# Generated deterministically by seda-macro-lef-normalizer-v1; recipe orfs-asap7-fakeram-m4-v1.
VERSION 5.8 ;
BUSBITCHARS "[]" ;
DIVIDERCHAR "/" ;

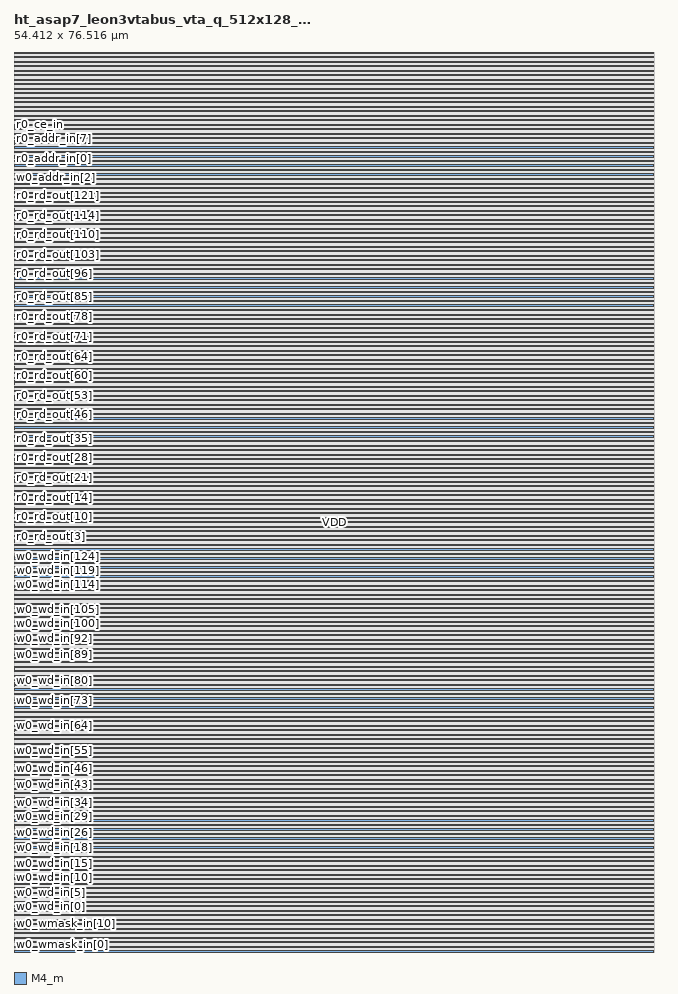
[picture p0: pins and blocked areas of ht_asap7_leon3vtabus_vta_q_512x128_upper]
MACRO ht_asap7_leon3vtabus_vta_q_512x128_upper
  FOREIGN ht_asap7_leon3vtabus_vta_q_512x128_upper 0 0 ;
  CLASS BLOCK ;
  ORIGIN 0 0 ;
  SIZE 54.412 BY 76.516 ;
  SYMMETRY X Y R90 ;
  PIN w0_wmask_in[0]
    DIRECTION INPUT ;
    USE SIGNAL ;
    SHAPE ABUTMENT ;
    PORT
      LAYER M4_m ;
      RECT 0 0.048 0.024 0.072 ;
    END
  END w0_wmask_in[0]
  PIN w0_wmask_in[1]
    DIRECTION INPUT ;
    USE SIGNAL ;
    SHAPE ABUTMENT ;
    PORT
      LAYER M4_m ;
      RECT 0 0.288 0.024 0.312 ;
    END
  END w0_wmask_in[1]
  PIN w0_wmask_in[2]
    DIRECTION INPUT ;
    USE SIGNAL ;
    SHAPE ABUTMENT ;
    PORT
      LAYER M4_m ;
      RECT 0 0.528 0.024 0.552 ;
    END
  END w0_wmask_in[2]
  PIN w0_wmask_in[3]
    DIRECTION INPUT ;
    USE SIGNAL ;
    SHAPE ABUTMENT ;
    PORT
      LAYER M4_m ;
      RECT 0 0.768 0.024 0.792 ;
    END
  END w0_wmask_in[3]
  PIN w0_wmask_in[4]
    DIRECTION INPUT ;
    USE SIGNAL ;
    SHAPE ABUTMENT ;
    PORT
      LAYER M4_m ;
      RECT 0 1.008 0.024 1.032 ;
    END
  END w0_wmask_in[4]
  PIN w0_wmask_in[5]
    DIRECTION INPUT ;
    USE SIGNAL ;
    SHAPE ABUTMENT ;
    PORT
      LAYER M4_m ;
      RECT 0 1.248 0.024 1.272 ;
    END
  END w0_wmask_in[5]
  PIN w0_wmask_in[6]
    DIRECTION INPUT ;
    USE SIGNAL ;
    SHAPE ABUTMENT ;
    PORT
      LAYER M4_m ;
      RECT 0 1.488 0.024 1.512 ;
    END
  END w0_wmask_in[6]
  PIN w0_wmask_in[7]
    DIRECTION INPUT ;
    USE SIGNAL ;
    SHAPE ABUTMENT ;
    PORT
      LAYER M4_m ;
      RECT 0 1.728 0.024 1.752 ;
    END
  END w0_wmask_in[7]
  PIN w0_wmask_in[8]
    DIRECTION INPUT ;
    USE SIGNAL ;
    SHAPE ABUTMENT ;
    PORT
      LAYER M4_m ;
      RECT 0 1.968 0.024 1.992 ;
    END
  END w0_wmask_in[8]
  PIN w0_wmask_in[9]
    DIRECTION INPUT ;
    USE SIGNAL ;
    SHAPE ABUTMENT ;
    PORT
      LAYER M4_m ;
      RECT 0 2.208 0.024 2.232 ;
    END
  END w0_wmask_in[9]
  PIN w0_wmask_in[10]
    DIRECTION INPUT ;
    USE SIGNAL ;
    SHAPE ABUTMENT ;
    PORT
      LAYER M4_m ;
      RECT 0 2.448 0.024 2.472 ;
    END
  END w0_wmask_in[10]
  PIN w0_wmask_in[11]
    DIRECTION INPUT ;
    USE SIGNAL ;
    SHAPE ABUTMENT ;
    PORT
      LAYER M4_m ;
      RECT 0 2.688 0.024 2.712 ;
    END
  END w0_wmask_in[11]
  PIN w0_wmask_in[12]
    DIRECTION INPUT ;
    USE SIGNAL ;
    SHAPE ABUTMENT ;
    PORT
      LAYER M4_m ;
      RECT 0 2.928 0.024 2.952 ;
    END
  END w0_wmask_in[12]
  PIN w0_wmask_in[13]
    DIRECTION INPUT ;
    USE SIGNAL ;
    SHAPE ABUTMENT ;
    PORT
      LAYER M4_m ;
      RECT 0 3.168 0.024 3.192 ;
    END
  END w0_wmask_in[13]
  PIN w0_wmask_in[14]
    DIRECTION INPUT ;
    USE SIGNAL ;
    SHAPE ABUTMENT ;
    PORT
      LAYER M4_m ;
      RECT 0 3.408 0.024 3.432 ;
    END
  END w0_wmask_in[14]
  PIN w0_wmask_in[15]
    DIRECTION INPUT ;
    USE SIGNAL ;
    SHAPE ABUTMENT ;
    PORT
      LAYER M4_m ;
      RECT 0 3.648 0.024 3.672 ;
    END
  END w0_wmask_in[15]
  PIN w0_wd_in[0]
    DIRECTION INPUT ;
    USE SIGNAL ;
    SHAPE ABUTMENT ;
    PORT
      LAYER M4_m ;
      RECT 0 3.888 0.024 3.912 ;
    END
  END w0_wd_in[0]
  PIN w0_wd_in[1]
    DIRECTION INPUT ;
    USE SIGNAL ;
    SHAPE ABUTMENT ;
    PORT
      LAYER M4_m ;
      RECT 0 4.128 0.024 4.152 ;
    END
  END w0_wd_in[1]
  PIN w0_wd_in[2]
    DIRECTION INPUT ;
    USE SIGNAL ;
    SHAPE ABUTMENT ;
    PORT
      LAYER M4_m ;
      RECT 0 4.368 0.024 4.392 ;
    END
  END w0_wd_in[2]
  PIN w0_wd_in[3]
    DIRECTION INPUT ;
    USE SIGNAL ;
    SHAPE ABUTMENT ;
    PORT
      LAYER M4_m ;
      RECT 0 4.608 0.024 4.632 ;
    END
  END w0_wd_in[3]
  PIN w0_wd_in[4]
    DIRECTION INPUT ;
    USE SIGNAL ;
    SHAPE ABUTMENT ;
    PORT
      LAYER M4_m ;
      RECT 0 4.848 0.024 4.872 ;
    END
  END w0_wd_in[4]
  PIN w0_wd_in[5]
    DIRECTION INPUT ;
    USE SIGNAL ;
    SHAPE ABUTMENT ;
    PORT
      LAYER M4_m ;
      RECT 0 5.088 0.024 5.112 ;
    END
  END w0_wd_in[5]
  PIN w0_wd_in[6]
    DIRECTION INPUT ;
    USE SIGNAL ;
    SHAPE ABUTMENT ;
    PORT
      LAYER M4_m ;
      RECT 0 5.328 0.024 5.352 ;
    END
  END w0_wd_in[6]
  PIN w0_wd_in[7]
    DIRECTION INPUT ;
    USE SIGNAL ;
    SHAPE ABUTMENT ;
    PORT
      LAYER M4_m ;
      RECT 0 5.568 0.024 5.592 ;
    END
  END w0_wd_in[7]
  PIN w0_wd_in[8]
    DIRECTION INPUT ;
    USE SIGNAL ;
    SHAPE ABUTMENT ;
    PORT
      LAYER M4_m ;
      RECT 0 5.808 0.024 5.832 ;
    END
  END w0_wd_in[8]
  PIN w0_wd_in[9]
    DIRECTION INPUT ;
    USE SIGNAL ;
    SHAPE ABUTMENT ;
    PORT
      LAYER M4_m ;
      RECT 0 6.048 0.024 6.072 ;
    END
  END w0_wd_in[9]
  PIN w0_wd_in[10]
    DIRECTION INPUT ;
    USE SIGNAL ;
    SHAPE ABUTMENT ;
    PORT
      LAYER M4_m ;
      RECT 0 6.288 0.024 6.312 ;
    END
  END w0_wd_in[10]
  PIN w0_wd_in[11]
    DIRECTION INPUT ;
    USE SIGNAL ;
    SHAPE ABUTMENT ;
    PORT
      LAYER M4_m ;
      RECT 0 6.528 0.024 6.552 ;
    END
  END w0_wd_in[11]
  PIN w0_wd_in[12]
    DIRECTION INPUT ;
    USE SIGNAL ;
    SHAPE ABUTMENT ;
    PORT
      LAYER M4_m ;
      RECT 0 6.768 0.024 6.792 ;
    END
  END w0_wd_in[12]
  PIN w0_wd_in[13]
    DIRECTION INPUT ;
    USE SIGNAL ;
    SHAPE ABUTMENT ;
    PORT
      LAYER M4_m ;
      RECT 0 7.008 0.024 7.032 ;
    END
  END w0_wd_in[13]
  PIN w0_wd_in[14]
    DIRECTION INPUT ;
    USE SIGNAL ;
    SHAPE ABUTMENT ;
    PORT
      LAYER M4_m ;
      RECT 0 7.248 0.024 7.272 ;
    END
  END w0_wd_in[14]
  PIN w0_wd_in[15]
    DIRECTION INPUT ;
    USE SIGNAL ;
    SHAPE ABUTMENT ;
    PORT
      LAYER M4_m ;
      RECT 0 7.488 0.024 7.512 ;
    END
  END w0_wd_in[15]
  PIN w0_wd_in[16]
    DIRECTION INPUT ;
    USE SIGNAL ;
    SHAPE ABUTMENT ;
    PORT
      LAYER M4_m ;
      RECT 0 7.728 0.024 7.752 ;
    END
  END w0_wd_in[16]
  PIN w0_wd_in[17]
    DIRECTION INPUT ;
    USE SIGNAL ;
    SHAPE ABUTMENT ;
    PORT
      LAYER M4_m ;
      RECT 0 7.968 0.024 7.992 ;
    END
  END w0_wd_in[17]
  PIN w0_wd_in[18]
    DIRECTION INPUT ;
    USE SIGNAL ;
    SHAPE ABUTMENT ;
    PORT
      LAYER M4_m ;
      RECT 0 8.208 0.024 8.232 ;
    END
  END w0_wd_in[18]
  PIN w0_wd_in[19]
    DIRECTION INPUT ;
    USE SIGNAL ;
    SHAPE ABUTMENT ;
    PORT
      LAYER M4_m ;
      RECT 0 8.448 0.024 8.472 ;
    END
  END w0_wd_in[19]
  PIN w0_wd_in[20]
    DIRECTION INPUT ;
    USE SIGNAL ;
    SHAPE ABUTMENT ;
    PORT
      LAYER M4_m ;
      RECT 0 8.688 0.024 8.712 ;
    END
  END w0_wd_in[20]
  PIN w0_wd_in[21]
    DIRECTION INPUT ;
    USE SIGNAL ;
    SHAPE ABUTMENT ;
    PORT
      LAYER M4_m ;
      RECT 0 8.928 0.024 8.952 ;
    END
  END w0_wd_in[21]
  PIN w0_wd_in[22]
    DIRECTION INPUT ;
    USE SIGNAL ;
    SHAPE ABUTMENT ;
    PORT
      LAYER M4_m ;
      RECT 0 9.168 0.024 9.192 ;
    END
  END w0_wd_in[22]
  PIN w0_wd_in[23]
    DIRECTION INPUT ;
    USE SIGNAL ;
    SHAPE ABUTMENT ;
    PORT
      LAYER M4_m ;
      RECT 0 9.408 0.024 9.432 ;
    END
  END w0_wd_in[23]
  PIN w0_wd_in[24]
    DIRECTION INPUT ;
    USE SIGNAL ;
    SHAPE ABUTMENT ;
    PORT
      LAYER M4_m ;
      RECT 0 9.648 0.024 9.672 ;
    END
  END w0_wd_in[24]
  PIN w0_wd_in[25]
    DIRECTION INPUT ;
    USE SIGNAL ;
    SHAPE ABUTMENT ;
    PORT
      LAYER M4_m ;
      RECT 0 9.888 0.024 9.912 ;
    END
  END w0_wd_in[25]
  PIN w0_wd_in[26]
    DIRECTION INPUT ;
    USE SIGNAL ;
    SHAPE ABUTMENT ;
    PORT
      LAYER M4_m ;
      RECT 0 10.128 0.024 10.152 ;
    END
  END w0_wd_in[26]
  PIN w0_wd_in[27]
    DIRECTION INPUT ;
    USE SIGNAL ;
    SHAPE ABUTMENT ;
    PORT
      LAYER M4_m ;
      RECT 0 10.368 0.024 10.392 ;
    END
  END w0_wd_in[27]
  PIN w0_wd_in[28]
    DIRECTION INPUT ;
    USE SIGNAL ;
    SHAPE ABUTMENT ;
    PORT
      LAYER M4_m ;
      RECT 0 10.608 0.024 10.632 ;
    END
  END w0_wd_in[28]
  PIN w0_wd_in[29]
    DIRECTION INPUT ;
    USE SIGNAL ;
    SHAPE ABUTMENT ;
    PORT
      LAYER M4_m ;
      RECT 0 10.848 0.024 10.872 ;
    END
  END w0_wd_in[29]
  PIN w0_wd_in[30]
    DIRECTION INPUT ;
    USE SIGNAL ;
    SHAPE ABUTMENT ;
    PORT
      LAYER M4_m ;
      RECT 0 11.088 0.024 11.112 ;
    END
  END w0_wd_in[30]
  PIN w0_wd_in[31]
    DIRECTION INPUT ;
    USE SIGNAL ;
    SHAPE ABUTMENT ;
    PORT
      LAYER M4_m ;
      RECT 0 11.328 0.024 11.352 ;
    END
  END w0_wd_in[31]
  PIN w0_wd_in[32]
    DIRECTION INPUT ;
    USE SIGNAL ;
    SHAPE ABUTMENT ;
    PORT
      LAYER M4_m ;
      RECT 0 11.568 0.024 11.592 ;
    END
  END w0_wd_in[32]
  PIN w0_wd_in[33]
    DIRECTION INPUT ;
    USE SIGNAL ;
    SHAPE ABUTMENT ;
    PORT
      LAYER M4_m ;
      RECT 0 11.808 0.024 11.832 ;
    END
  END w0_wd_in[33]
  PIN w0_wd_in[34]
    DIRECTION INPUT ;
    USE SIGNAL ;
    SHAPE ABUTMENT ;
    PORT
      LAYER M4_m ;
      RECT 0 12.048 0.024 12.072 ;
    END
  END w0_wd_in[34]
  PIN w0_wd_in[35]
    DIRECTION INPUT ;
    USE SIGNAL ;
    SHAPE ABUTMENT ;
    PORT
      LAYER M4_m ;
      RECT 0 12.288 0.024 12.312 ;
    END
  END w0_wd_in[35]
  PIN w0_wd_in[36]
    DIRECTION INPUT ;
    USE SIGNAL ;
    SHAPE ABUTMENT ;
    PORT
      LAYER M4_m ;
      RECT 0 12.528 0.024 12.552 ;
    END
  END w0_wd_in[36]
  PIN w0_wd_in[37]
    DIRECTION INPUT ;
    USE SIGNAL ;
    SHAPE ABUTMENT ;
    PORT
      LAYER M4_m ;
      RECT 0 12.768 0.024 12.792 ;
    END
  END w0_wd_in[37]
  PIN w0_wd_in[38]
    DIRECTION INPUT ;
    USE SIGNAL ;
    SHAPE ABUTMENT ;
    PORT
      LAYER M4_m ;
      RECT 0 13.008 0.024 13.032 ;
    END
  END w0_wd_in[38]
  PIN w0_wd_in[39]
    DIRECTION INPUT ;
    USE SIGNAL ;
    SHAPE ABUTMENT ;
    PORT
      LAYER M4_m ;
      RECT 0 13.248 0.024 13.272 ;
    END
  END w0_wd_in[39]
  PIN w0_wd_in[40]
    DIRECTION INPUT ;
    USE SIGNAL ;
    SHAPE ABUTMENT ;
    PORT
      LAYER M4_m ;
      RECT 0 13.488 0.024 13.512 ;
    END
  END w0_wd_in[40]
  PIN w0_wd_in[41]
    DIRECTION INPUT ;
    USE SIGNAL ;
    SHAPE ABUTMENT ;
    PORT
      LAYER M4_m ;
      RECT 0 13.728 0.024 13.752 ;
    END
  END w0_wd_in[41]
  PIN w0_wd_in[42]
    DIRECTION INPUT ;
    USE SIGNAL ;
    SHAPE ABUTMENT ;
    PORT
      LAYER M4_m ;
      RECT 0 13.968 0.024 13.992 ;
    END
  END w0_wd_in[42]
  PIN w0_wd_in[43]
    DIRECTION INPUT ;
    USE SIGNAL ;
    SHAPE ABUTMENT ;
    PORT
      LAYER M4_m ;
      RECT 0 14.208 0.024 14.232 ;
    END
  END w0_wd_in[43]
  PIN w0_wd_in[44]
    DIRECTION INPUT ;
    USE SIGNAL ;
    SHAPE ABUTMENT ;
    PORT
      LAYER M4_m ;
      RECT 0 14.448 0.024 14.472 ;
    END
  END w0_wd_in[44]
  PIN w0_wd_in[45]
    DIRECTION INPUT ;
    USE SIGNAL ;
    SHAPE ABUTMENT ;
    PORT
      LAYER M4_m ;
      RECT 0 14.688 0.024 14.712 ;
    END
  END w0_wd_in[45]
  PIN w0_wd_in[46]
    DIRECTION INPUT ;
    USE SIGNAL ;
    SHAPE ABUTMENT ;
    PORT
      LAYER M4_m ;
      RECT 0 14.928 0.024 14.952 ;
    END
  END w0_wd_in[46]
  PIN w0_wd_in[47]
    DIRECTION INPUT ;
    USE SIGNAL ;
    SHAPE ABUTMENT ;
    PORT
      LAYER M4_m ;
      RECT 0 15.168 0.024 15.192 ;
    END
  END w0_wd_in[47]
  PIN w0_wd_in[48]
    DIRECTION INPUT ;
    USE SIGNAL ;
    SHAPE ABUTMENT ;
    PORT
      LAYER M4_m ;
      RECT 0 15.408 0.024 15.432 ;
    END
  END w0_wd_in[48]
  PIN w0_wd_in[49]
    DIRECTION INPUT ;
    USE SIGNAL ;
    SHAPE ABUTMENT ;
    PORT
      LAYER M4_m ;
      RECT 0 15.648 0.024 15.672 ;
    END
  END w0_wd_in[49]
  PIN w0_wd_in[50]
    DIRECTION INPUT ;
    USE SIGNAL ;
    SHAPE ABUTMENT ;
    PORT
      LAYER M4_m ;
      RECT 0 15.888 0.024 15.912 ;
    END
  END w0_wd_in[50]
  PIN w0_wd_in[51]
    DIRECTION INPUT ;
    USE SIGNAL ;
    SHAPE ABUTMENT ;
    PORT
      LAYER M4_m ;
      RECT 0 16.128 0.024 16.152 ;
    END
  END w0_wd_in[51]
  PIN w0_wd_in[52]
    DIRECTION INPUT ;
    USE SIGNAL ;
    SHAPE ABUTMENT ;
    PORT
      LAYER M4_m ;
      RECT 0 16.368 0.024 16.392 ;
    END
  END w0_wd_in[52]
  PIN w0_wd_in[53]
    DIRECTION INPUT ;
    USE SIGNAL ;
    SHAPE ABUTMENT ;
    PORT
      LAYER M4_m ;
      RECT 0 16.608 0.024 16.632 ;
    END
  END w0_wd_in[53]
  PIN w0_wd_in[54]
    DIRECTION INPUT ;
    USE SIGNAL ;
    SHAPE ABUTMENT ;
    PORT
      LAYER M4_m ;
      RECT 0 16.848 0.024 16.872 ;
    END
  END w0_wd_in[54]
  PIN w0_wd_in[55]
    DIRECTION INPUT ;
    USE SIGNAL ;
    SHAPE ABUTMENT ;
    PORT
      LAYER M4_m ;
      RECT 0 17.088 0.024 17.112 ;
    END
  END w0_wd_in[55]
  PIN w0_wd_in[56]
    DIRECTION INPUT ;
    USE SIGNAL ;
    SHAPE ABUTMENT ;
    PORT
      LAYER M4_m ;
      RECT 0 17.328 0.024 17.352 ;
    END
  END w0_wd_in[56]
  PIN w0_wd_in[57]
    DIRECTION INPUT ;
    USE SIGNAL ;
    SHAPE ABUTMENT ;
    PORT
      LAYER M4_m ;
      RECT 0 17.568 0.024 17.592 ;
    END
  END w0_wd_in[57]
  PIN w0_wd_in[58]
    DIRECTION INPUT ;
    USE SIGNAL ;
    SHAPE ABUTMENT ;
    PORT
      LAYER M4_m ;
      RECT 0 17.808 0.024 17.832 ;
    END
  END w0_wd_in[58]
  PIN w0_wd_in[59]
    DIRECTION INPUT ;
    USE SIGNAL ;
    SHAPE ABUTMENT ;
    PORT
      LAYER M4_m ;
      RECT 0 18.048 0.024 18.072 ;
    END
  END w0_wd_in[59]
  PIN w0_wd_in[60]
    DIRECTION INPUT ;
    USE SIGNAL ;
    SHAPE ABUTMENT ;
    PORT
      LAYER M4_m ;
      RECT 0 18.288 0.024 18.312 ;
    END
  END w0_wd_in[60]
  PIN w0_wd_in[61]
    DIRECTION INPUT ;
    USE SIGNAL ;
    SHAPE ABUTMENT ;
    PORT
      LAYER M4_m ;
      RECT 0 18.528 0.024 18.552 ;
    END
  END w0_wd_in[61]
  PIN w0_wd_in[62]
    DIRECTION INPUT ;
    USE SIGNAL ;
    SHAPE ABUTMENT ;
    PORT
      LAYER M4_m ;
      RECT 0 18.768 0.024 18.792 ;
    END
  END w0_wd_in[62]
  PIN w0_wd_in[63]
    DIRECTION INPUT ;
    USE SIGNAL ;
    SHAPE ABUTMENT ;
    PORT
      LAYER M4_m ;
      RECT 0 19.008 0.024 19.032 ;
    END
  END w0_wd_in[63]
  PIN w0_wd_in[64]
    DIRECTION INPUT ;
    USE SIGNAL ;
    SHAPE ABUTMENT ;
    PORT
      LAYER M4_m ;
      RECT 0 19.248 0.024 19.272 ;
    END
  END w0_wd_in[64]
  PIN w0_wd_in[65]
    DIRECTION INPUT ;
    USE SIGNAL ;
    SHAPE ABUTMENT ;
    PORT
      LAYER M4_m ;
      RECT 0 19.488 0.024 19.512 ;
    END
  END w0_wd_in[65]
  PIN w0_wd_in[66]
    DIRECTION INPUT ;
    USE SIGNAL ;
    SHAPE ABUTMENT ;
    PORT
      LAYER M4_m ;
      RECT 0 19.728 0.024 19.752 ;
    END
  END w0_wd_in[66]
  PIN w0_wd_in[67]
    DIRECTION INPUT ;
    USE SIGNAL ;
    SHAPE ABUTMENT ;
    PORT
      LAYER M4_m ;
      RECT 0 19.968 0.024 19.992 ;
    END
  END w0_wd_in[67]
  PIN w0_wd_in[68]
    DIRECTION INPUT ;
    USE SIGNAL ;
    SHAPE ABUTMENT ;
    PORT
      LAYER M4_m ;
      RECT 0 20.208 0.024 20.232 ;
    END
  END w0_wd_in[68]
  PIN w0_wd_in[69]
    DIRECTION INPUT ;
    USE SIGNAL ;
    SHAPE ABUTMENT ;
    PORT
      LAYER M4_m ;
      RECT 0 20.448 0.024 20.472 ;
    END
  END w0_wd_in[69]
  PIN w0_wd_in[70]
    DIRECTION INPUT ;
    USE SIGNAL ;
    SHAPE ABUTMENT ;
    PORT
      LAYER M4_m ;
      RECT 0 20.688 0.024 20.712 ;
    END
  END w0_wd_in[70]
  PIN w0_wd_in[71]
    DIRECTION INPUT ;
    USE SIGNAL ;
    SHAPE ABUTMENT ;
    PORT
      LAYER M4_m ;
      RECT 0 20.928 0.024 20.952 ;
    END
  END w0_wd_in[71]
  PIN w0_wd_in[72]
    DIRECTION INPUT ;
    USE SIGNAL ;
    SHAPE ABUTMENT ;
    PORT
      LAYER M4_m ;
      RECT 0 21.168 0.024 21.192 ;
    END
  END w0_wd_in[72]
  PIN w0_wd_in[73]
    DIRECTION INPUT ;
    USE SIGNAL ;
    SHAPE ABUTMENT ;
    PORT
      LAYER M4_m ;
      RECT 0 21.408 0.024 21.432 ;
    END
  END w0_wd_in[73]
  PIN w0_wd_in[74]
    DIRECTION INPUT ;
    USE SIGNAL ;
    SHAPE ABUTMENT ;
    PORT
      LAYER M4_m ;
      RECT 0 21.648 0.024 21.672 ;
    END
  END w0_wd_in[74]
  PIN w0_wd_in[75]
    DIRECTION INPUT ;
    USE SIGNAL ;
    SHAPE ABUTMENT ;
    PORT
      LAYER M4_m ;
      RECT 0 21.888 0.024 21.912 ;
    END
  END w0_wd_in[75]
  PIN w0_wd_in[76]
    DIRECTION INPUT ;
    USE SIGNAL ;
    SHAPE ABUTMENT ;
    PORT
      LAYER M4_m ;
      RECT 0 22.128 0.024 22.152 ;
    END
  END w0_wd_in[76]
  PIN w0_wd_in[77]
    DIRECTION INPUT ;
    USE SIGNAL ;
    SHAPE ABUTMENT ;
    PORT
      LAYER M4_m ;
      RECT 0 22.368 0.024 22.392 ;
    END
  END w0_wd_in[77]
  PIN w0_wd_in[78]
    DIRECTION INPUT ;
    USE SIGNAL ;
    SHAPE ABUTMENT ;
    PORT
      LAYER M4_m ;
      RECT 0 22.608 0.024 22.632 ;
    END
  END w0_wd_in[78]
  PIN w0_wd_in[79]
    DIRECTION INPUT ;
    USE SIGNAL ;
    SHAPE ABUTMENT ;
    PORT
      LAYER M4_m ;
      RECT 0 22.848 0.024 22.872 ;
    END
  END w0_wd_in[79]
  PIN w0_wd_in[80]
    DIRECTION INPUT ;
    USE SIGNAL ;
    SHAPE ABUTMENT ;
    PORT
      LAYER M4_m ;
      RECT 0 23.088 0.024 23.112 ;
    END
  END w0_wd_in[80]
  PIN w0_wd_in[81]
    DIRECTION INPUT ;
    USE SIGNAL ;
    SHAPE ABUTMENT ;
    PORT
      LAYER M4_m ;
      RECT 0 23.328 0.024 23.352 ;
    END
  END w0_wd_in[81]
  PIN w0_wd_in[82]
    DIRECTION INPUT ;
    USE SIGNAL ;
    SHAPE ABUTMENT ;
    PORT
      LAYER M4_m ;
      RECT 0 23.568 0.024 23.592 ;
    END
  END w0_wd_in[82]
  PIN w0_wd_in[83]
    DIRECTION INPUT ;
    USE SIGNAL ;
    SHAPE ABUTMENT ;
    PORT
      LAYER M4_m ;
      RECT 0 23.808 0.024 23.832 ;
    END
  END w0_wd_in[83]
  PIN w0_wd_in[84]
    DIRECTION INPUT ;
    USE SIGNAL ;
    SHAPE ABUTMENT ;
    PORT
      LAYER M4_m ;
      RECT 0 24.048 0.024 24.072 ;
    END
  END w0_wd_in[84]
  PIN w0_wd_in[85]
    DIRECTION INPUT ;
    USE SIGNAL ;
    SHAPE ABUTMENT ;
    PORT
      LAYER M4_m ;
      RECT 0 24.288 0.024 24.312 ;
    END
  END w0_wd_in[85]
  PIN w0_wd_in[86]
    DIRECTION INPUT ;
    USE SIGNAL ;
    SHAPE ABUTMENT ;
    PORT
      LAYER M4_m ;
      RECT 0 24.528 0.024 24.552 ;
    END
  END w0_wd_in[86]
  PIN w0_wd_in[87]
    DIRECTION INPUT ;
    USE SIGNAL ;
    SHAPE ABUTMENT ;
    PORT
      LAYER M4_m ;
      RECT 0 24.768 0.024 24.792 ;
    END
  END w0_wd_in[87]
  PIN w0_wd_in[88]
    DIRECTION INPUT ;
    USE SIGNAL ;
    SHAPE ABUTMENT ;
    PORT
      LAYER M4_m ;
      RECT 0 25.008 0.024 25.032 ;
    END
  END w0_wd_in[88]
  PIN w0_wd_in[89]
    DIRECTION INPUT ;
    USE SIGNAL ;
    SHAPE ABUTMENT ;
    PORT
      LAYER M4_m ;
      RECT 0 25.248 0.024 25.272 ;
    END
  END w0_wd_in[89]
  PIN w0_wd_in[90]
    DIRECTION INPUT ;
    USE SIGNAL ;
    SHAPE ABUTMENT ;
    PORT
      LAYER M4_m ;
      RECT 0 25.488 0.024 25.512 ;
    END
  END w0_wd_in[90]
  PIN w0_wd_in[91]
    DIRECTION INPUT ;
    USE SIGNAL ;
    SHAPE ABUTMENT ;
    PORT
      LAYER M4_m ;
      RECT 0 25.728 0.024 25.752 ;
    END
  END w0_wd_in[91]
  PIN w0_wd_in[92]
    DIRECTION INPUT ;
    USE SIGNAL ;
    SHAPE ABUTMENT ;
    PORT
      LAYER M4_m ;
      RECT 0 25.968 0.024 25.992 ;
    END
  END w0_wd_in[92]
  PIN w0_wd_in[93]
    DIRECTION INPUT ;
    USE SIGNAL ;
    SHAPE ABUTMENT ;
    PORT
      LAYER M4_m ;
      RECT 0 26.208 0.024 26.232 ;
    END
  END w0_wd_in[93]
  PIN w0_wd_in[94]
    DIRECTION INPUT ;
    USE SIGNAL ;
    SHAPE ABUTMENT ;
    PORT
      LAYER M4_m ;
      RECT 0 26.448 0.024 26.472 ;
    END
  END w0_wd_in[94]
  PIN w0_wd_in[95]
    DIRECTION INPUT ;
    USE SIGNAL ;
    SHAPE ABUTMENT ;
    PORT
      LAYER M4_m ;
      RECT 0 26.688 0.024 26.712 ;
    END
  END w0_wd_in[95]
  PIN w0_wd_in[96]
    DIRECTION INPUT ;
    USE SIGNAL ;
    SHAPE ABUTMENT ;
    PORT
      LAYER M4_m ;
      RECT 0 26.928 0.024 26.952 ;
    END
  END w0_wd_in[96]
  PIN w0_wd_in[97]
    DIRECTION INPUT ;
    USE SIGNAL ;
    SHAPE ABUTMENT ;
    PORT
      LAYER M4_m ;
      RECT 0 27.168 0.024 27.192 ;
    END
  END w0_wd_in[97]
  PIN w0_wd_in[98]
    DIRECTION INPUT ;
    USE SIGNAL ;
    SHAPE ABUTMENT ;
    PORT
      LAYER M4_m ;
      RECT 0 27.408 0.024 27.432 ;
    END
  END w0_wd_in[98]
  PIN w0_wd_in[99]
    DIRECTION INPUT ;
    USE SIGNAL ;
    SHAPE ABUTMENT ;
    PORT
      LAYER M4_m ;
      RECT 0 27.648 0.024 27.672 ;
    END
  END w0_wd_in[99]
  PIN w0_wd_in[100]
    DIRECTION INPUT ;
    USE SIGNAL ;
    SHAPE ABUTMENT ;
    PORT
      LAYER M4_m ;
      RECT 0 27.888 0.024 27.912 ;
    END
  END w0_wd_in[100]
  PIN w0_wd_in[101]
    DIRECTION INPUT ;
    USE SIGNAL ;
    SHAPE ABUTMENT ;
    PORT
      LAYER M4_m ;
      RECT 0 28.128 0.024 28.152 ;
    END
  END w0_wd_in[101]
  PIN w0_wd_in[102]
    DIRECTION INPUT ;
    USE SIGNAL ;
    SHAPE ABUTMENT ;
    PORT
      LAYER M4_m ;
      RECT 0 28.368 0.024 28.392 ;
    END
  END w0_wd_in[102]
  PIN w0_wd_in[103]
    DIRECTION INPUT ;
    USE SIGNAL ;
    SHAPE ABUTMENT ;
    PORT
      LAYER M4_m ;
      RECT 0 28.608 0.024 28.632 ;
    END
  END w0_wd_in[103]
  PIN w0_wd_in[104]
    DIRECTION INPUT ;
    USE SIGNAL ;
    SHAPE ABUTMENT ;
    PORT
      LAYER M4_m ;
      RECT 0 28.848 0.024 28.872 ;
    END
  END w0_wd_in[104]
  PIN w0_wd_in[105]
    DIRECTION INPUT ;
    USE SIGNAL ;
    SHAPE ABUTMENT ;
    PORT
      LAYER M4_m ;
      RECT 0 29.088 0.024 29.112 ;
    END
  END w0_wd_in[105]
  PIN w0_wd_in[106]
    DIRECTION INPUT ;
    USE SIGNAL ;
    SHAPE ABUTMENT ;
    PORT
      LAYER M4_m ;
      RECT 0 29.328 0.024 29.352 ;
    END
  END w0_wd_in[106]
  PIN w0_wd_in[107]
    DIRECTION INPUT ;
    USE SIGNAL ;
    SHAPE ABUTMENT ;
    PORT
      LAYER M4_m ;
      RECT 0 29.568 0.024 29.592 ;
    END
  END w0_wd_in[107]
  PIN w0_wd_in[108]
    DIRECTION INPUT ;
    USE SIGNAL ;
    SHAPE ABUTMENT ;
    PORT
      LAYER M4_m ;
      RECT 0 29.808 0.024 29.832 ;
    END
  END w0_wd_in[108]
  PIN w0_wd_in[109]
    DIRECTION INPUT ;
    USE SIGNAL ;
    SHAPE ABUTMENT ;
    PORT
      LAYER M4_m ;
      RECT 0 30.048 0.024 30.072 ;
    END
  END w0_wd_in[109]
  PIN w0_wd_in[110]
    DIRECTION INPUT ;
    USE SIGNAL ;
    SHAPE ABUTMENT ;
    PORT
      LAYER M4_m ;
      RECT 0 30.288 0.024 30.312 ;
    END
  END w0_wd_in[110]
  PIN w0_wd_in[111]
    DIRECTION INPUT ;
    USE SIGNAL ;
    SHAPE ABUTMENT ;
    PORT
      LAYER M4_m ;
      RECT 0 30.528 0.024 30.552 ;
    END
  END w0_wd_in[111]
  PIN w0_wd_in[112]
    DIRECTION INPUT ;
    USE SIGNAL ;
    SHAPE ABUTMENT ;
    PORT
      LAYER M4_m ;
      RECT 0 30.768 0.024 30.792 ;
    END
  END w0_wd_in[112]
  PIN w0_wd_in[113]
    DIRECTION INPUT ;
    USE SIGNAL ;
    SHAPE ABUTMENT ;
    PORT
      LAYER M4_m ;
      RECT 0 31.008 0.024 31.032 ;
    END
  END w0_wd_in[113]
  PIN w0_wd_in[114]
    DIRECTION INPUT ;
    USE SIGNAL ;
    SHAPE ABUTMENT ;
    PORT
      LAYER M4_m ;
      RECT 0 31.248 0.024 31.272 ;
    END
  END w0_wd_in[114]
  PIN w0_wd_in[115]
    DIRECTION INPUT ;
    USE SIGNAL ;
    SHAPE ABUTMENT ;
    PORT
      LAYER M4_m ;
      RECT 0 31.488 0.024 31.512 ;
    END
  END w0_wd_in[115]
  PIN w0_wd_in[116]
    DIRECTION INPUT ;
    USE SIGNAL ;
    SHAPE ABUTMENT ;
    PORT
      LAYER M4_m ;
      RECT 0 31.728 0.024 31.752 ;
    END
  END w0_wd_in[116]
  PIN w0_wd_in[117]
    DIRECTION INPUT ;
    USE SIGNAL ;
    SHAPE ABUTMENT ;
    PORT
      LAYER M4_m ;
      RECT 0 31.968 0.024 31.992 ;
    END
  END w0_wd_in[117]
  PIN w0_wd_in[118]
    DIRECTION INPUT ;
    USE SIGNAL ;
    SHAPE ABUTMENT ;
    PORT
      LAYER M4_m ;
      RECT 0 32.208 0.024 32.232 ;
    END
  END w0_wd_in[118]
  PIN w0_wd_in[119]
    DIRECTION INPUT ;
    USE SIGNAL ;
    SHAPE ABUTMENT ;
    PORT
      LAYER M4_m ;
      RECT 0 32.448 0.024 32.472 ;
    END
  END w0_wd_in[119]
  PIN w0_wd_in[120]
    DIRECTION INPUT ;
    USE SIGNAL ;
    SHAPE ABUTMENT ;
    PORT
      LAYER M4_m ;
      RECT 0 32.688 0.024 32.712 ;
    END
  END w0_wd_in[120]
  PIN w0_wd_in[121]
    DIRECTION INPUT ;
    USE SIGNAL ;
    SHAPE ABUTMENT ;
    PORT
      LAYER M4_m ;
      RECT 0 32.928 0.024 32.952 ;
    END
  END w0_wd_in[121]
  PIN w0_wd_in[122]
    DIRECTION INPUT ;
    USE SIGNAL ;
    SHAPE ABUTMENT ;
    PORT
      LAYER M4_m ;
      RECT 0 33.168 0.024 33.192 ;
    END
  END w0_wd_in[122]
  PIN w0_wd_in[123]
    DIRECTION INPUT ;
    USE SIGNAL ;
    SHAPE ABUTMENT ;
    PORT
      LAYER M4_m ;
      RECT 0 33.408 0.024 33.432 ;
    END
  END w0_wd_in[123]
  PIN w0_wd_in[124]
    DIRECTION INPUT ;
    USE SIGNAL ;
    SHAPE ABUTMENT ;
    PORT
      LAYER M4_m ;
      RECT 0 33.648 0.024 33.672 ;
    END
  END w0_wd_in[124]
  PIN w0_wd_in[125]
    DIRECTION INPUT ;
    USE SIGNAL ;
    SHAPE ABUTMENT ;
    PORT
      LAYER M4_m ;
      RECT 0 33.888 0.024 33.912 ;
    END
  END w0_wd_in[125]
  PIN w0_wd_in[126]
    DIRECTION INPUT ;
    USE SIGNAL ;
    SHAPE ABUTMENT ;
    PORT
      LAYER M4_m ;
      RECT 0 34.128 0.024 34.152 ;
    END
  END w0_wd_in[126]
  PIN w0_wd_in[127]
    DIRECTION INPUT ;
    USE SIGNAL ;
    SHAPE ABUTMENT ;
    PORT
      LAYER M4_m ;
      RECT 0 34.368 0.024 34.392 ;
    END
  END w0_wd_in[127]
  PIN r0_rd_out[0]
    DIRECTION OUTPUT ;
    USE SIGNAL ;
    SHAPE ABUTMENT ;
    PORT
      LAYER M4_m ;
      RECT 0 34.608 0.024 34.632 ;
    END
  END r0_rd_out[0]
  PIN r0_rd_out[1]
    DIRECTION OUTPUT ;
    USE SIGNAL ;
    SHAPE ABUTMENT ;
    PORT
      LAYER M4_m ;
      RECT 0 34.848 0.024 34.872 ;
    END
  END r0_rd_out[1]
  PIN r0_rd_out[2]
    DIRECTION OUTPUT ;
    USE SIGNAL ;
    SHAPE ABUTMENT ;
    PORT
      LAYER M4_m ;
      RECT 0 35.088 0.024 35.112 ;
    END
  END r0_rd_out[2]
  PIN r0_rd_out[3]
    DIRECTION OUTPUT ;
    USE SIGNAL ;
    SHAPE ABUTMENT ;
    PORT
      LAYER M4_m ;
      RECT 0 35.328 0.024 35.352 ;
    END
  END r0_rd_out[3]
  PIN r0_rd_out[4]
    DIRECTION OUTPUT ;
    USE SIGNAL ;
    SHAPE ABUTMENT ;
    PORT
      LAYER M4_m ;
      RECT 0 35.568 0.024 35.592 ;
    END
  END r0_rd_out[4]
  PIN r0_rd_out[5]
    DIRECTION OUTPUT ;
    USE SIGNAL ;
    SHAPE ABUTMENT ;
    PORT
      LAYER M4_m ;
      RECT 0 35.808 0.024 35.832 ;
    END
  END r0_rd_out[5]
  PIN r0_rd_out[6]
    DIRECTION OUTPUT ;
    USE SIGNAL ;
    SHAPE ABUTMENT ;
    PORT
      LAYER M4_m ;
      RECT 0 36.048 0.024 36.072 ;
    END
  END r0_rd_out[6]
  PIN r0_rd_out[7]
    DIRECTION OUTPUT ;
    USE SIGNAL ;
    SHAPE ABUTMENT ;
    PORT
      LAYER M4_m ;
      RECT 0 36.288 0.024 36.312 ;
    END
  END r0_rd_out[7]
  PIN r0_rd_out[8]
    DIRECTION OUTPUT ;
    USE SIGNAL ;
    SHAPE ABUTMENT ;
    PORT
      LAYER M4_m ;
      RECT 0 36.528 0.024 36.552 ;
    END
  END r0_rd_out[8]
  PIN r0_rd_out[9]
    DIRECTION OUTPUT ;
    USE SIGNAL ;
    SHAPE ABUTMENT ;
    PORT
      LAYER M4_m ;
      RECT 0 36.768 0.024 36.792 ;
    END
  END r0_rd_out[9]
  PIN r0_rd_out[10]
    DIRECTION OUTPUT ;
    USE SIGNAL ;
    SHAPE ABUTMENT ;
    PORT
      LAYER M4_m ;
      RECT 0 37.008 0.024 37.032 ;
    END
  END r0_rd_out[10]
  PIN r0_rd_out[11]
    DIRECTION OUTPUT ;
    USE SIGNAL ;
    SHAPE ABUTMENT ;
    PORT
      LAYER M4_m ;
      RECT 0 37.248 0.024 37.272 ;
    END
  END r0_rd_out[11]
  PIN r0_rd_out[12]
    DIRECTION OUTPUT ;
    USE SIGNAL ;
    SHAPE ABUTMENT ;
    PORT
      LAYER M4_m ;
      RECT 0 37.488 0.024 37.512 ;
    END
  END r0_rd_out[12]
  PIN r0_rd_out[13]
    DIRECTION OUTPUT ;
    USE SIGNAL ;
    SHAPE ABUTMENT ;
    PORT
      LAYER M4_m ;
      RECT 0 37.728 0.024 37.752 ;
    END
  END r0_rd_out[13]
  PIN r0_rd_out[14]
    DIRECTION OUTPUT ;
    USE SIGNAL ;
    SHAPE ABUTMENT ;
    PORT
      LAYER M4_m ;
      RECT 0 37.968 0.024 37.992 ;
    END
  END r0_rd_out[14]
  PIN r0_rd_out[15]
    DIRECTION OUTPUT ;
    USE SIGNAL ;
    SHAPE ABUTMENT ;
    PORT
      LAYER M4_m ;
      RECT 0 38.208 0.024 38.232 ;
    END
  END r0_rd_out[15]
  PIN r0_rd_out[16]
    DIRECTION OUTPUT ;
    USE SIGNAL ;
    SHAPE ABUTMENT ;
    PORT
      LAYER M4_m ;
      RECT 0 38.448 0.024 38.472 ;
    END
  END r0_rd_out[16]
  PIN r0_rd_out[17]
    DIRECTION OUTPUT ;
    USE SIGNAL ;
    SHAPE ABUTMENT ;
    PORT
      LAYER M4_m ;
      RECT 0 38.688 0.024 38.712 ;
    END
  END r0_rd_out[17]
  PIN r0_rd_out[18]
    DIRECTION OUTPUT ;
    USE SIGNAL ;
    SHAPE ABUTMENT ;
    PORT
      LAYER M4_m ;
      RECT 0 38.928 0.024 38.952 ;
    END
  END r0_rd_out[18]
  PIN r0_rd_out[19]
    DIRECTION OUTPUT ;
    USE SIGNAL ;
    SHAPE ABUTMENT ;
    PORT
      LAYER M4_m ;
      RECT 0 39.168 0.024 39.192 ;
    END
  END r0_rd_out[19]
  PIN r0_rd_out[20]
    DIRECTION OUTPUT ;
    USE SIGNAL ;
    SHAPE ABUTMENT ;
    PORT
      LAYER M4_m ;
      RECT 0 39.408 0.024 39.432 ;
    END
  END r0_rd_out[20]
  PIN r0_rd_out[21]
    DIRECTION OUTPUT ;
    USE SIGNAL ;
    SHAPE ABUTMENT ;
    PORT
      LAYER M4_m ;
      RECT 0 39.648 0.024 39.672 ;
    END
  END r0_rd_out[21]
  PIN r0_rd_out[22]
    DIRECTION OUTPUT ;
    USE SIGNAL ;
    SHAPE ABUTMENT ;
    PORT
      LAYER M4_m ;
      RECT 0 39.888 0.024 39.912 ;
    END
  END r0_rd_out[22]
  PIN r0_rd_out[23]
    DIRECTION OUTPUT ;
    USE SIGNAL ;
    SHAPE ABUTMENT ;
    PORT
      LAYER M4_m ;
      RECT 0 40.128 0.024 40.152 ;
    END
  END r0_rd_out[23]
  PIN r0_rd_out[24]
    DIRECTION OUTPUT ;
    USE SIGNAL ;
    SHAPE ABUTMENT ;
    PORT
      LAYER M4_m ;
      RECT 0 40.368 0.024 40.392 ;
    END
  END r0_rd_out[24]
  PIN r0_rd_out[25]
    DIRECTION OUTPUT ;
    USE SIGNAL ;
    SHAPE ABUTMENT ;
    PORT
      LAYER M4_m ;
      RECT 0 40.608 0.024 40.632 ;
    END
  END r0_rd_out[25]
  PIN r0_rd_out[26]
    DIRECTION OUTPUT ;
    USE SIGNAL ;
    SHAPE ABUTMENT ;
    PORT
      LAYER M4_m ;
      RECT 0 40.848 0.024 40.872 ;
    END
  END r0_rd_out[26]
  PIN r0_rd_out[27]
    DIRECTION OUTPUT ;
    USE SIGNAL ;
    SHAPE ABUTMENT ;
    PORT
      LAYER M4_m ;
      RECT 0 41.088 0.024 41.112 ;
    END
  END r0_rd_out[27]
  PIN r0_rd_out[28]
    DIRECTION OUTPUT ;
    USE SIGNAL ;
    SHAPE ABUTMENT ;
    PORT
      LAYER M4_m ;
      RECT 0 41.328 0.024 41.352 ;
    END
  END r0_rd_out[28]
  PIN r0_rd_out[29]
    DIRECTION OUTPUT ;
    USE SIGNAL ;
    SHAPE ABUTMENT ;
    PORT
      LAYER M4_m ;
      RECT 0 41.568 0.024 41.592 ;
    END
  END r0_rd_out[29]
  PIN r0_rd_out[30]
    DIRECTION OUTPUT ;
    USE SIGNAL ;
    SHAPE ABUTMENT ;
    PORT
      LAYER M4_m ;
      RECT 0 41.808 0.024 41.832 ;
    END
  END r0_rd_out[30]
  PIN r0_rd_out[31]
    DIRECTION OUTPUT ;
    USE SIGNAL ;
    SHAPE ABUTMENT ;
    PORT
      LAYER M4_m ;
      RECT 0 42.048 0.024 42.072 ;
    END
  END r0_rd_out[31]
  PIN r0_rd_out[32]
    DIRECTION OUTPUT ;
    USE SIGNAL ;
    SHAPE ABUTMENT ;
    PORT
      LAYER M4_m ;
      RECT 0 42.288 0.024 42.312 ;
    END
  END r0_rd_out[32]
  PIN r0_rd_out[33]
    DIRECTION OUTPUT ;
    USE SIGNAL ;
    SHAPE ABUTMENT ;
    PORT
      LAYER M4_m ;
      RECT 0 42.528 0.024 42.552 ;
    END
  END r0_rd_out[33]
  PIN r0_rd_out[34]
    DIRECTION OUTPUT ;
    USE SIGNAL ;
    SHAPE ABUTMENT ;
    PORT
      LAYER M4_m ;
      RECT 0 42.768 0.024 42.792 ;
    END
  END r0_rd_out[34]
  PIN r0_rd_out[35]
    DIRECTION OUTPUT ;
    USE SIGNAL ;
    SHAPE ABUTMENT ;
    PORT
      LAYER M4_m ;
      RECT 0 43.008 0.024 43.032 ;
    END
  END r0_rd_out[35]
  PIN r0_rd_out[36]
    DIRECTION OUTPUT ;
    USE SIGNAL ;
    SHAPE ABUTMENT ;
    PORT
      LAYER M4_m ;
      RECT 0 43.248 0.024 43.272 ;
    END
  END r0_rd_out[36]
  PIN r0_rd_out[37]
    DIRECTION OUTPUT ;
    USE SIGNAL ;
    SHAPE ABUTMENT ;
    PORT
      LAYER M4_m ;
      RECT 0 43.488 0.024 43.512 ;
    END
  END r0_rd_out[37]
  PIN r0_rd_out[38]
    DIRECTION OUTPUT ;
    USE SIGNAL ;
    SHAPE ABUTMENT ;
    PORT
      LAYER M4_m ;
      RECT 0 43.728 0.024 43.752 ;
    END
  END r0_rd_out[38]
  PIN r0_rd_out[39]
    DIRECTION OUTPUT ;
    USE SIGNAL ;
    SHAPE ABUTMENT ;
    PORT
      LAYER M4_m ;
      RECT 0 43.968 0.024 43.992 ;
    END
  END r0_rd_out[39]
  PIN r0_rd_out[40]
    DIRECTION OUTPUT ;
    USE SIGNAL ;
    SHAPE ABUTMENT ;
    PORT
      LAYER M4_m ;
      RECT 0 44.208 0.024 44.232 ;
    END
  END r0_rd_out[40]
  PIN r0_rd_out[41]
    DIRECTION OUTPUT ;
    USE SIGNAL ;
    SHAPE ABUTMENT ;
    PORT
      LAYER M4_m ;
      RECT 0 44.448 0.024 44.472 ;
    END
  END r0_rd_out[41]
  PIN r0_rd_out[42]
    DIRECTION OUTPUT ;
    USE SIGNAL ;
    SHAPE ABUTMENT ;
    PORT
      LAYER M4_m ;
      RECT 0 44.688 0.024 44.712 ;
    END
  END r0_rd_out[42]
  PIN r0_rd_out[43]
    DIRECTION OUTPUT ;
    USE SIGNAL ;
    SHAPE ABUTMENT ;
    PORT
      LAYER M4_m ;
      RECT 0 44.928 0.024 44.952 ;
    END
  END r0_rd_out[43]
  PIN r0_rd_out[44]
    DIRECTION OUTPUT ;
    USE SIGNAL ;
    SHAPE ABUTMENT ;
    PORT
      LAYER M4_m ;
      RECT 0 45.168 0.024 45.192 ;
    END
  END r0_rd_out[44]
  PIN r0_rd_out[45]
    DIRECTION OUTPUT ;
    USE SIGNAL ;
    SHAPE ABUTMENT ;
    PORT
      LAYER M4_m ;
      RECT 0 45.408 0.024 45.432 ;
    END
  END r0_rd_out[45]
  PIN r0_rd_out[46]
    DIRECTION OUTPUT ;
    USE SIGNAL ;
    SHAPE ABUTMENT ;
    PORT
      LAYER M4_m ;
      RECT 0 45.648 0.024 45.672 ;
    END
  END r0_rd_out[46]
  PIN r0_rd_out[47]
    DIRECTION OUTPUT ;
    USE SIGNAL ;
    SHAPE ABUTMENT ;
    PORT
      LAYER M4_m ;
      RECT 0 45.888 0.024 45.912 ;
    END
  END r0_rd_out[47]
  PIN r0_rd_out[48]
    DIRECTION OUTPUT ;
    USE SIGNAL ;
    SHAPE ABUTMENT ;
    PORT
      LAYER M4_m ;
      RECT 0 46.128 0.024 46.152 ;
    END
  END r0_rd_out[48]
  PIN r0_rd_out[49]
    DIRECTION OUTPUT ;
    USE SIGNAL ;
    SHAPE ABUTMENT ;
    PORT
      LAYER M4_m ;
      RECT 0 46.368 0.024 46.392 ;
    END
  END r0_rd_out[49]
  PIN r0_rd_out[50]
    DIRECTION OUTPUT ;
    USE SIGNAL ;
    SHAPE ABUTMENT ;
    PORT
      LAYER M4_m ;
      RECT 0 46.608 0.024 46.632 ;
    END
  END r0_rd_out[50]
  PIN r0_rd_out[51]
    DIRECTION OUTPUT ;
    USE SIGNAL ;
    SHAPE ABUTMENT ;
    PORT
      LAYER M4_m ;
      RECT 0 46.848 0.024 46.872 ;
    END
  END r0_rd_out[51]
  PIN r0_rd_out[52]
    DIRECTION OUTPUT ;
    USE SIGNAL ;
    SHAPE ABUTMENT ;
    PORT
      LAYER M4_m ;
      RECT 0 47.088 0.024 47.112 ;
    END
  END r0_rd_out[52]
  PIN r0_rd_out[53]
    DIRECTION OUTPUT ;
    USE SIGNAL ;
    SHAPE ABUTMENT ;
    PORT
      LAYER M4_m ;
      RECT 0 47.328 0.024 47.352 ;
    END
  END r0_rd_out[53]
  PIN r0_rd_out[54]
    DIRECTION OUTPUT ;
    USE SIGNAL ;
    SHAPE ABUTMENT ;
    PORT
      LAYER M4_m ;
      RECT 0 47.568 0.024 47.592 ;
    END
  END r0_rd_out[54]
  PIN r0_rd_out[55]
    DIRECTION OUTPUT ;
    USE SIGNAL ;
    SHAPE ABUTMENT ;
    PORT
      LAYER M4_m ;
      RECT 0 47.808 0.024 47.832 ;
    END
  END r0_rd_out[55]
  PIN r0_rd_out[56]
    DIRECTION OUTPUT ;
    USE SIGNAL ;
    SHAPE ABUTMENT ;
    PORT
      LAYER M4_m ;
      RECT 0 48.048 0.024 48.072 ;
    END
  END r0_rd_out[56]
  PIN r0_rd_out[57]
    DIRECTION OUTPUT ;
    USE SIGNAL ;
    SHAPE ABUTMENT ;
    PORT
      LAYER M4_m ;
      RECT 0 48.288 0.024 48.312 ;
    END
  END r0_rd_out[57]
  PIN r0_rd_out[58]
    DIRECTION OUTPUT ;
    USE SIGNAL ;
    SHAPE ABUTMENT ;
    PORT
      LAYER M4_m ;
      RECT 0 48.528 0.024 48.552 ;
    END
  END r0_rd_out[58]
  PIN r0_rd_out[59]
    DIRECTION OUTPUT ;
    USE SIGNAL ;
    SHAPE ABUTMENT ;
    PORT
      LAYER M4_m ;
      RECT 0 48.768 0.024 48.792 ;
    END
  END r0_rd_out[59]
  PIN r0_rd_out[60]
    DIRECTION OUTPUT ;
    USE SIGNAL ;
    SHAPE ABUTMENT ;
    PORT
      LAYER M4_m ;
      RECT 0 49.008 0.024 49.032 ;
    END
  END r0_rd_out[60]
  PIN r0_rd_out[61]
    DIRECTION OUTPUT ;
    USE SIGNAL ;
    SHAPE ABUTMENT ;
    PORT
      LAYER M4_m ;
      RECT 0 49.248 0.024 49.272 ;
    END
  END r0_rd_out[61]
  PIN r0_rd_out[62]
    DIRECTION OUTPUT ;
    USE SIGNAL ;
    SHAPE ABUTMENT ;
    PORT
      LAYER M4_m ;
      RECT 0 49.488 0.024 49.512 ;
    END
  END r0_rd_out[62]
  PIN r0_rd_out[63]
    DIRECTION OUTPUT ;
    USE SIGNAL ;
    SHAPE ABUTMENT ;
    PORT
      LAYER M4_m ;
      RECT 0 49.728 0.024 49.752 ;
    END
  END r0_rd_out[63]
  PIN r0_rd_out[64]
    DIRECTION OUTPUT ;
    USE SIGNAL ;
    SHAPE ABUTMENT ;
    PORT
      LAYER M4_m ;
      RECT 0 49.968 0.024 49.992 ;
    END
  END r0_rd_out[64]
  PIN r0_rd_out[65]
    DIRECTION OUTPUT ;
    USE SIGNAL ;
    SHAPE ABUTMENT ;
    PORT
      LAYER M4_m ;
      RECT 0 50.208 0.024 50.232 ;
    END
  END r0_rd_out[65]
  PIN r0_rd_out[66]
    DIRECTION OUTPUT ;
    USE SIGNAL ;
    SHAPE ABUTMENT ;
    PORT
      LAYER M4_m ;
      RECT 0 50.448 0.024 50.472 ;
    END
  END r0_rd_out[66]
  PIN r0_rd_out[67]
    DIRECTION OUTPUT ;
    USE SIGNAL ;
    SHAPE ABUTMENT ;
    PORT
      LAYER M4_m ;
      RECT 0 50.688 0.024 50.712 ;
    END
  END r0_rd_out[67]
  PIN r0_rd_out[68]
    DIRECTION OUTPUT ;
    USE SIGNAL ;
    SHAPE ABUTMENT ;
    PORT
      LAYER M4_m ;
      RECT 0 50.928 0.024 50.952 ;
    END
  END r0_rd_out[68]
  PIN r0_rd_out[69]
    DIRECTION OUTPUT ;
    USE SIGNAL ;
    SHAPE ABUTMENT ;
    PORT
      LAYER M4_m ;
      RECT 0 51.168 0.024 51.192 ;
    END
  END r0_rd_out[69]
  PIN r0_rd_out[70]
    DIRECTION OUTPUT ;
    USE SIGNAL ;
    SHAPE ABUTMENT ;
    PORT
      LAYER M4_m ;
      RECT 0 51.408 0.024 51.432 ;
    END
  END r0_rd_out[70]
  PIN r0_rd_out[71]
    DIRECTION OUTPUT ;
    USE SIGNAL ;
    SHAPE ABUTMENT ;
    PORT
      LAYER M4_m ;
      RECT 0 51.648 0.024 51.672 ;
    END
  END r0_rd_out[71]
  PIN r0_rd_out[72]
    DIRECTION OUTPUT ;
    USE SIGNAL ;
    SHAPE ABUTMENT ;
    PORT
      LAYER M4_m ;
      RECT 0 51.888 0.024 51.912 ;
    END
  END r0_rd_out[72]
  PIN r0_rd_out[73]
    DIRECTION OUTPUT ;
    USE SIGNAL ;
    SHAPE ABUTMENT ;
    PORT
      LAYER M4_m ;
      RECT 0 52.128 0.024 52.152 ;
    END
  END r0_rd_out[73]
  PIN r0_rd_out[74]
    DIRECTION OUTPUT ;
    USE SIGNAL ;
    SHAPE ABUTMENT ;
    PORT
      LAYER M4_m ;
      RECT 0 52.368 0.024 52.392 ;
    END
  END r0_rd_out[74]
  PIN r0_rd_out[75]
    DIRECTION OUTPUT ;
    USE SIGNAL ;
    SHAPE ABUTMENT ;
    PORT
      LAYER M4_m ;
      RECT 0 52.608 0.024 52.632 ;
    END
  END r0_rd_out[75]
  PIN r0_rd_out[76]
    DIRECTION OUTPUT ;
    USE SIGNAL ;
    SHAPE ABUTMENT ;
    PORT
      LAYER M4_m ;
      RECT 0 52.848 0.024 52.872 ;
    END
  END r0_rd_out[76]
  PIN r0_rd_out[77]
    DIRECTION OUTPUT ;
    USE SIGNAL ;
    SHAPE ABUTMENT ;
    PORT
      LAYER M4_m ;
      RECT 0 53.088 0.024 53.112 ;
    END
  END r0_rd_out[77]
  PIN r0_rd_out[78]
    DIRECTION OUTPUT ;
    USE SIGNAL ;
    SHAPE ABUTMENT ;
    PORT
      LAYER M4_m ;
      RECT 0 53.328 0.024 53.352 ;
    END
  END r0_rd_out[78]
  PIN r0_rd_out[79]
    DIRECTION OUTPUT ;
    USE SIGNAL ;
    SHAPE ABUTMENT ;
    PORT
      LAYER M4_m ;
      RECT 0 53.568 0.024 53.592 ;
    END
  END r0_rd_out[79]
  PIN r0_rd_out[80]
    DIRECTION OUTPUT ;
    USE SIGNAL ;
    SHAPE ABUTMENT ;
    PORT
      LAYER M4_m ;
      RECT 0 53.808 0.024 53.832 ;
    END
  END r0_rd_out[80]
  PIN r0_rd_out[81]
    DIRECTION OUTPUT ;
    USE SIGNAL ;
    SHAPE ABUTMENT ;
    PORT
      LAYER M4_m ;
      RECT 0 54.048 0.024 54.072 ;
    END
  END r0_rd_out[81]
  PIN r0_rd_out[82]
    DIRECTION OUTPUT ;
    USE SIGNAL ;
    SHAPE ABUTMENT ;
    PORT
      LAYER M4_m ;
      RECT 0 54.288 0.024 54.312 ;
    END
  END r0_rd_out[82]
  PIN r0_rd_out[83]
    DIRECTION OUTPUT ;
    USE SIGNAL ;
    SHAPE ABUTMENT ;
    PORT
      LAYER M4_m ;
      RECT 0 54.528 0.024 54.552 ;
    END
  END r0_rd_out[83]
  PIN r0_rd_out[84]
    DIRECTION OUTPUT ;
    USE SIGNAL ;
    SHAPE ABUTMENT ;
    PORT
      LAYER M4_m ;
      RECT 0 54.768 0.024 54.792 ;
    END
  END r0_rd_out[84]
  PIN r0_rd_out[85]
    DIRECTION OUTPUT ;
    USE SIGNAL ;
    SHAPE ABUTMENT ;
    PORT
      LAYER M4_m ;
      RECT 0 55.008 0.024 55.032 ;
    END
  END r0_rd_out[85]
  PIN r0_rd_out[86]
    DIRECTION OUTPUT ;
    USE SIGNAL ;
    SHAPE ABUTMENT ;
    PORT
      LAYER M4_m ;
      RECT 0 55.248 0.024 55.272 ;
    END
  END r0_rd_out[86]
  PIN r0_rd_out[87]
    DIRECTION OUTPUT ;
    USE SIGNAL ;
    SHAPE ABUTMENT ;
    PORT
      LAYER M4_m ;
      RECT 0 55.488 0.024 55.512 ;
    END
  END r0_rd_out[87]
  PIN r0_rd_out[88]
    DIRECTION OUTPUT ;
    USE SIGNAL ;
    SHAPE ABUTMENT ;
    PORT
      LAYER M4_m ;
      RECT 0 55.728 0.024 55.752 ;
    END
  END r0_rd_out[88]
  PIN r0_rd_out[89]
    DIRECTION OUTPUT ;
    USE SIGNAL ;
    SHAPE ABUTMENT ;
    PORT
      LAYER M4_m ;
      RECT 0 55.968 0.024 55.992 ;
    END
  END r0_rd_out[89]
  PIN r0_rd_out[90]
    DIRECTION OUTPUT ;
    USE SIGNAL ;
    SHAPE ABUTMENT ;
    PORT
      LAYER M4_m ;
      RECT 0 56.208 0.024 56.232 ;
    END
  END r0_rd_out[90]
  PIN r0_rd_out[91]
    DIRECTION OUTPUT ;
    USE SIGNAL ;
    SHAPE ABUTMENT ;
    PORT
      LAYER M4_m ;
      RECT 0 56.448 0.024 56.472 ;
    END
  END r0_rd_out[91]
  PIN r0_rd_out[92]
    DIRECTION OUTPUT ;
    USE SIGNAL ;
    SHAPE ABUTMENT ;
    PORT
      LAYER M4_m ;
      RECT 0 56.688 0.024 56.712 ;
    END
  END r0_rd_out[92]
  PIN r0_rd_out[93]
    DIRECTION OUTPUT ;
    USE SIGNAL ;
    SHAPE ABUTMENT ;
    PORT
      LAYER M4_m ;
      RECT 0 56.928 0.024 56.952 ;
    END
  END r0_rd_out[93]
  PIN r0_rd_out[94]
    DIRECTION OUTPUT ;
    USE SIGNAL ;
    SHAPE ABUTMENT ;
    PORT
      LAYER M4_m ;
      RECT 0 57.168 0.024 57.192 ;
    END
  END r0_rd_out[94]
  PIN r0_rd_out[95]
    DIRECTION OUTPUT ;
    USE SIGNAL ;
    SHAPE ABUTMENT ;
    PORT
      LAYER M4_m ;
      RECT 0 57.408 0.024 57.432 ;
    END
  END r0_rd_out[95]
  PIN r0_rd_out[96]
    DIRECTION OUTPUT ;
    USE SIGNAL ;
    SHAPE ABUTMENT ;
    PORT
      LAYER M4_m ;
      RECT 0 57.648 0.024 57.672 ;
    END
  END r0_rd_out[96]
  PIN r0_rd_out[97]
    DIRECTION OUTPUT ;
    USE SIGNAL ;
    SHAPE ABUTMENT ;
    PORT
      LAYER M4_m ;
      RECT 0 57.888 0.024 57.912 ;
    END
  END r0_rd_out[97]
  PIN r0_rd_out[98]
    DIRECTION OUTPUT ;
    USE SIGNAL ;
    SHAPE ABUTMENT ;
    PORT
      LAYER M4_m ;
      RECT 0 58.128 0.024 58.152 ;
    END
  END r0_rd_out[98]
  PIN r0_rd_out[99]
    DIRECTION OUTPUT ;
    USE SIGNAL ;
    SHAPE ABUTMENT ;
    PORT
      LAYER M4_m ;
      RECT 0 58.368 0.024 58.392 ;
    END
  END r0_rd_out[99]
  PIN r0_rd_out[100]
    DIRECTION OUTPUT ;
    USE SIGNAL ;
    SHAPE ABUTMENT ;
    PORT
      LAYER M4_m ;
      RECT 0 58.608 0.024 58.632 ;
    END
  END r0_rd_out[100]
  PIN r0_rd_out[101]
    DIRECTION OUTPUT ;
    USE SIGNAL ;
    SHAPE ABUTMENT ;
    PORT
      LAYER M4_m ;
      RECT 0 58.848 0.024 58.872 ;
    END
  END r0_rd_out[101]
  PIN r0_rd_out[102]
    DIRECTION OUTPUT ;
    USE SIGNAL ;
    SHAPE ABUTMENT ;
    PORT
      LAYER M4_m ;
      RECT 0 59.088 0.024 59.112 ;
    END
  END r0_rd_out[102]
  PIN r0_rd_out[103]
    DIRECTION OUTPUT ;
    USE SIGNAL ;
    SHAPE ABUTMENT ;
    PORT
      LAYER M4_m ;
      RECT 0 59.328 0.024 59.352 ;
    END
  END r0_rd_out[103]
  PIN r0_rd_out[104]
    DIRECTION OUTPUT ;
    USE SIGNAL ;
    SHAPE ABUTMENT ;
    PORT
      LAYER M4_m ;
      RECT 0 59.568 0.024 59.592 ;
    END
  END r0_rd_out[104]
  PIN r0_rd_out[105]
    DIRECTION OUTPUT ;
    USE SIGNAL ;
    SHAPE ABUTMENT ;
    PORT
      LAYER M4_m ;
      RECT 0 59.808 0.024 59.832 ;
    END
  END r0_rd_out[105]
  PIN r0_rd_out[106]
    DIRECTION OUTPUT ;
    USE SIGNAL ;
    SHAPE ABUTMENT ;
    PORT
      LAYER M4_m ;
      RECT 0 60.048 0.024 60.072 ;
    END
  END r0_rd_out[106]
  PIN r0_rd_out[107]
    DIRECTION OUTPUT ;
    USE SIGNAL ;
    SHAPE ABUTMENT ;
    PORT
      LAYER M4_m ;
      RECT 0 60.288 0.024 60.312 ;
    END
  END r0_rd_out[107]
  PIN r0_rd_out[108]
    DIRECTION OUTPUT ;
    USE SIGNAL ;
    SHAPE ABUTMENT ;
    PORT
      LAYER M4_m ;
      RECT 0 60.528 0.024 60.552 ;
    END
  END r0_rd_out[108]
  PIN r0_rd_out[109]
    DIRECTION OUTPUT ;
    USE SIGNAL ;
    SHAPE ABUTMENT ;
    PORT
      LAYER M4_m ;
      RECT 0 60.768 0.024 60.792 ;
    END
  END r0_rd_out[109]
  PIN r0_rd_out[110]
    DIRECTION OUTPUT ;
    USE SIGNAL ;
    SHAPE ABUTMENT ;
    PORT
      LAYER M4_m ;
      RECT 0 61.008 0.024 61.032 ;
    END
  END r0_rd_out[110]
  PIN r0_rd_out[111]
    DIRECTION OUTPUT ;
    USE SIGNAL ;
    SHAPE ABUTMENT ;
    PORT
      LAYER M4_m ;
      RECT 0 61.248 0.024 61.272 ;
    END
  END r0_rd_out[111]
  PIN r0_rd_out[112]
    DIRECTION OUTPUT ;
    USE SIGNAL ;
    SHAPE ABUTMENT ;
    PORT
      LAYER M4_m ;
      RECT 0 61.488 0.024 61.512 ;
    END
  END r0_rd_out[112]
  PIN r0_rd_out[113]
    DIRECTION OUTPUT ;
    USE SIGNAL ;
    SHAPE ABUTMENT ;
    PORT
      LAYER M4_m ;
      RECT 0 61.728 0.024 61.752 ;
    END
  END r0_rd_out[113]
  PIN r0_rd_out[114]
    DIRECTION OUTPUT ;
    USE SIGNAL ;
    SHAPE ABUTMENT ;
    PORT
      LAYER M4_m ;
      RECT 0 61.968 0.024 61.992 ;
    END
  END r0_rd_out[114]
  PIN r0_rd_out[115]
    DIRECTION OUTPUT ;
    USE SIGNAL ;
    SHAPE ABUTMENT ;
    PORT
      LAYER M4_m ;
      RECT 0 62.208 0.024 62.232 ;
    END
  END r0_rd_out[115]
  PIN r0_rd_out[116]
    DIRECTION OUTPUT ;
    USE SIGNAL ;
    SHAPE ABUTMENT ;
    PORT
      LAYER M4_m ;
      RECT 0 62.448 0.024 62.472 ;
    END
  END r0_rd_out[116]
  PIN r0_rd_out[117]
    DIRECTION OUTPUT ;
    USE SIGNAL ;
    SHAPE ABUTMENT ;
    PORT
      LAYER M4_m ;
      RECT 0 62.688 0.024 62.712 ;
    END
  END r0_rd_out[117]
  PIN r0_rd_out[118]
    DIRECTION OUTPUT ;
    USE SIGNAL ;
    SHAPE ABUTMENT ;
    PORT
      LAYER M4_m ;
      RECT 0 62.928 0.024 62.952 ;
    END
  END r0_rd_out[118]
  PIN r0_rd_out[119]
    DIRECTION OUTPUT ;
    USE SIGNAL ;
    SHAPE ABUTMENT ;
    PORT
      LAYER M4_m ;
      RECT 0 63.168 0.024 63.192 ;
    END
  END r0_rd_out[119]
  PIN r0_rd_out[120]
    DIRECTION OUTPUT ;
    USE SIGNAL ;
    SHAPE ABUTMENT ;
    PORT
      LAYER M4_m ;
      RECT 0 63.408 0.024 63.432 ;
    END
  END r0_rd_out[120]
  PIN r0_rd_out[121]
    DIRECTION OUTPUT ;
    USE SIGNAL ;
    SHAPE ABUTMENT ;
    PORT
      LAYER M4_m ;
      RECT 0 63.648 0.024 63.672 ;
    END
  END r0_rd_out[121]
  PIN r0_rd_out[122]
    DIRECTION OUTPUT ;
    USE SIGNAL ;
    SHAPE ABUTMENT ;
    PORT
      LAYER M4_m ;
      RECT 0 63.888 0.024 63.912 ;
    END
  END r0_rd_out[122]
  PIN r0_rd_out[123]
    DIRECTION OUTPUT ;
    USE SIGNAL ;
    SHAPE ABUTMENT ;
    PORT
      LAYER M4_m ;
      RECT 0 64.128 0.024 64.152 ;
    END
  END r0_rd_out[123]
  PIN r0_rd_out[124]
    DIRECTION OUTPUT ;
    USE SIGNAL ;
    SHAPE ABUTMENT ;
    PORT
      LAYER M4_m ;
      RECT 0 64.368 0.024 64.392 ;
    END
  END r0_rd_out[124]
  PIN r0_rd_out[125]
    DIRECTION OUTPUT ;
    USE SIGNAL ;
    SHAPE ABUTMENT ;
    PORT
      LAYER M4_m ;
      RECT 0 64.608 0.024 64.632 ;
    END
  END r0_rd_out[125]
  PIN r0_rd_out[126]
    DIRECTION OUTPUT ;
    USE SIGNAL ;
    SHAPE ABUTMENT ;
    PORT
      LAYER M4_m ;
      RECT 0 64.848 0.024 64.872 ;
    END
  END r0_rd_out[126]
  PIN r0_rd_out[127]
    DIRECTION OUTPUT ;
    USE SIGNAL ;
    SHAPE ABUTMENT ;
    PORT
      LAYER M4_m ;
      RECT 0 65.088 0.024 65.112 ;
    END
  END r0_rd_out[127]
  PIN w0_addr_in[0]
    DIRECTION INPUT ;
    USE SIGNAL ;
    SHAPE ABUTMENT ;
    PORT
      LAYER M4_m ;
      RECT 0 65.328 0.024 65.352 ;
    END
  END w0_addr_in[0]
  PIN w0_addr_in[1]
    DIRECTION INPUT ;
    USE SIGNAL ;
    SHAPE ABUTMENT ;
    PORT
      LAYER M4_m ;
      RECT 0 65.568 0.024 65.592 ;
    END
  END w0_addr_in[1]
  PIN w0_addr_in[2]
    DIRECTION INPUT ;
    USE SIGNAL ;
    SHAPE ABUTMENT ;
    PORT
      LAYER M4_m ;
      RECT 0 65.808 0.024 65.832 ;
    END
  END w0_addr_in[2]
  PIN w0_addr_in[3]
    DIRECTION INPUT ;
    USE SIGNAL ;
    SHAPE ABUTMENT ;
    PORT
      LAYER M4_m ;
      RECT 0 66.048 0.024 66.072 ;
    END
  END w0_addr_in[3]
  PIN w0_addr_in[4]
    DIRECTION INPUT ;
    USE SIGNAL ;
    SHAPE ABUTMENT ;
    PORT
      LAYER M4_m ;
      RECT 0 66.288 0.024 66.312 ;
    END
  END w0_addr_in[4]
  PIN w0_addr_in[5]
    DIRECTION INPUT ;
    USE SIGNAL ;
    SHAPE ABUTMENT ;
    PORT
      LAYER M4_m ;
      RECT 0 66.528 0.024 66.552 ;
    END
  END w0_addr_in[5]
  PIN w0_addr_in[6]
    DIRECTION INPUT ;
    USE SIGNAL ;
    SHAPE ABUTMENT ;
    PORT
      LAYER M4_m ;
      RECT 0 66.768 0.024 66.792 ;
    END
  END w0_addr_in[6]
  PIN w0_addr_in[7]
    DIRECTION INPUT ;
    USE SIGNAL ;
    SHAPE ABUTMENT ;
    PORT
      LAYER M4_m ;
      RECT 0 67.008 0.024 67.032 ;
    END
  END w0_addr_in[7]
  PIN w0_addr_in[8]
    DIRECTION INPUT ;
    USE SIGNAL ;
    SHAPE ABUTMENT ;
    PORT
      LAYER M4_m ;
      RECT 0 67.248 0.024 67.272 ;
    END
  END w0_addr_in[8]
  PIN r0_addr_in[0]
    DIRECTION INPUT ;
    USE SIGNAL ;
    SHAPE ABUTMENT ;
    PORT
      LAYER M4_m ;
      RECT 0 67.488 0.024 67.512 ;
    END
  END r0_addr_in[0]
  PIN r0_addr_in[1]
    DIRECTION INPUT ;
    USE SIGNAL ;
    SHAPE ABUTMENT ;
    PORT
      LAYER M4_m ;
      RECT 0 67.728 0.024 67.752 ;
    END
  END r0_addr_in[1]
  PIN r0_addr_in[2]
    DIRECTION INPUT ;
    USE SIGNAL ;
    SHAPE ABUTMENT ;
    PORT
      LAYER M4_m ;
      RECT 0 67.968 0.024 67.992 ;
    END
  END r0_addr_in[2]
  PIN r0_addr_in[3]
    DIRECTION INPUT ;
    USE SIGNAL ;
    SHAPE ABUTMENT ;
    PORT
      LAYER M4_m ;
      RECT 0 68.208 0.024 68.232 ;
    END
  END r0_addr_in[3]
  PIN r0_addr_in[4]
    DIRECTION INPUT ;
    USE SIGNAL ;
    SHAPE ABUTMENT ;
    PORT
      LAYER M4_m ;
      RECT 0 68.448 0.024 68.472 ;
    END
  END r0_addr_in[4]
  PIN r0_addr_in[5]
    DIRECTION INPUT ;
    USE SIGNAL ;
    SHAPE ABUTMENT ;
    PORT
      LAYER M4_m ;
      RECT 0 68.688 0.024 68.712 ;
    END
  END r0_addr_in[5]
  PIN r0_addr_in[6]
    DIRECTION INPUT ;
    USE SIGNAL ;
    SHAPE ABUTMENT ;
    PORT
      LAYER M4_m ;
      RECT 0 68.928 0.024 68.952 ;
    END
  END r0_addr_in[6]
  PIN r0_addr_in[7]
    DIRECTION INPUT ;
    USE SIGNAL ;
    SHAPE ABUTMENT ;
    PORT
      LAYER M4_m ;
      RECT 0 69.168 0.024 69.192 ;
    END
  END r0_addr_in[7]
  PIN r0_addr_in[8]
    DIRECTION INPUT ;
    USE SIGNAL ;
    SHAPE ABUTMENT ;
    PORT
      LAYER M4_m ;
      RECT 0 69.408 0.024 69.432 ;
    END
  END r0_addr_in[8]
  PIN w0_we_in
    DIRECTION INPUT ;
    USE SIGNAL ;
    SHAPE ABUTMENT ;
    PORT
      LAYER M4_m ;
      RECT 0 69.648 0.024 69.672 ;
    END
  END w0_we_in
  PIN w0_ce_in
    DIRECTION INPUT ;
    USE SIGNAL ;
    SHAPE ABUTMENT ;
    PORT
      LAYER M4_m ;
      RECT 0 69.888 0.024 69.912 ;
    END
  END w0_ce_in
  PIN w0_clk
    DIRECTION INPUT ;
    USE SIGNAL ;
    SHAPE ABUTMENT ;
    PORT
      LAYER M4_m ;
      RECT 0 70.128 0.024 70.152 ;
    END
  END w0_clk
  PIN r0_ce_in
    DIRECTION INPUT ;
    USE SIGNAL ;
    SHAPE ABUTMENT ;
    PORT
      LAYER M4_m ;
      RECT 0 70.368 0.024 70.392 ;
    END
  END r0_ce_in
  PIN r0_clk
    DIRECTION INPUT ;
    USE SIGNAL ;
    SHAPE ABUTMENT ;
    PORT
      LAYER M4_m ;
      RECT 0 70.608 0.024 70.632 ;
    END
  END r0_clk
  PIN VSS
    DIRECTION INOUT ;
    USE GROUND ;
    PORT
      LAYER M4_m ;
      RECT 0.048 0 54.364 0.096 ;
      RECT 0.048 0.768 54.364 0.864 ;
      RECT 0.048 1.536 54.364 1.632 ;
      RECT 0.048 2.304 54.364 2.4 ;
      RECT 0.048 3.072 54.364 3.168 ;
      RECT 0.048 3.84 54.364 3.936 ;
      RECT 0.048 4.608 54.364 4.704 ;
      RECT 0.048 5.376 54.364 5.472 ;
      RECT 0.048 6.144 54.364 6.24 ;
      RECT 0.048 6.912 54.364 7.008 ;
      RECT 0.048 7.68 54.364 7.776 ;
      RECT 0.048 8.448 54.364 8.544 ;
      RECT 0.048 9.216 54.364 9.312 ;
      RECT 0.048 9.984 54.364 10.08 ;
      RECT 0.048 10.752 54.364 10.848 ;
      RECT 0.048 11.52 54.364 11.616 ;
      RECT 0.048 12.288 54.364 12.384 ;
      RECT 0.048 13.056 54.364 13.152 ;
      RECT 0.048 13.824 54.364 13.92 ;
      RECT 0.048 14.592 54.364 14.688 ;
      RECT 0.048 15.36 54.364 15.456 ;
      RECT 0.048 16.128 54.364 16.224 ;
      RECT 0.048 16.896 54.364 16.992 ;
      RECT 0.048 17.664 54.364 17.76 ;
      RECT 0.048 18.432 54.364 18.528 ;
      RECT 0.048 19.2 54.364 19.296 ;
      RECT 0.048 19.968 54.364 20.064 ;
      RECT 0.048 20.736 54.364 20.832 ;
      RECT 0.048 21.504 54.364 21.6 ;
      RECT 0.048 22.272 54.364 22.368 ;
      RECT 0.048 23.04 54.364 23.136 ;
      RECT 0.048 23.808 54.364 23.904 ;
      RECT 0.048 24.576 54.364 24.672 ;
      RECT 0.048 25.344 54.364 25.44 ;
      RECT 0.048 26.112 54.364 26.208 ;
      RECT 0.048 26.88 54.364 26.976 ;
      RECT 0.048 27.648 54.364 27.744 ;
      RECT 0.048 28.416 54.364 28.512 ;
      RECT 0.048 29.184 54.364 29.28 ;
      RECT 0.048 29.952 54.364 30.048 ;
      RECT 0.048 30.72 54.364 30.816 ;
      RECT 0.048 31.488 54.364 31.584 ;
      RECT 0.048 32.256 54.364 32.352 ;
      RECT 0.048 33.024 54.364 33.12 ;
      RECT 0.048 33.792 54.364 33.888 ;
      RECT 0.048 34.56 54.364 34.656 ;
      RECT 0.048 35.328 54.364 35.424 ;
      RECT 0.048 36.096 54.364 36.192 ;
      RECT 0.048 36.864 54.364 36.96 ;
      RECT 0.048 37.632 54.364 37.728 ;
      RECT 0.048 38.4 54.364 38.496 ;
      RECT 0.048 39.168 54.364 39.264 ;
      RECT 0.048 39.936 54.364 40.032 ;
      RECT 0.048 40.704 54.364 40.8 ;
      RECT 0.048 41.472 54.364 41.568 ;
      RECT 0.048 42.24 54.364 42.336 ;
      RECT 0.048 43.008 54.364 43.104 ;
      RECT 0.048 43.776 54.364 43.872 ;
      RECT 0.048 44.544 54.364 44.64 ;
      RECT 0.048 45.312 54.364 45.408 ;
      RECT 0.048 46.08 54.364 46.176 ;
      RECT 0.048 46.848 54.364 46.944 ;
      RECT 0.048 47.616 54.364 47.712 ;
      RECT 0.048 48.384 54.364 48.48 ;
      RECT 0.048 49.152 54.364 49.248 ;
      RECT 0.048 49.92 54.364 50.016 ;
      RECT 0.048 50.688 54.364 50.784 ;
      RECT 0.048 51.456 54.364 51.552 ;
      RECT 0.048 52.224 54.364 52.32 ;
      RECT 0.048 52.992 54.364 53.088 ;
      RECT 0.048 53.76 54.364 53.856 ;
      RECT 0.048 54.528 54.364 54.624 ;
      RECT 0.048 55.296 54.364 55.392 ;
      RECT 0.048 56.064 54.364 56.16 ;
      RECT 0.048 56.832 54.364 56.928 ;
      RECT 0.048 57.6 54.364 57.696 ;
      RECT 0.048 58.368 54.364 58.464 ;
      RECT 0.048 59.136 54.364 59.232 ;
      RECT 0.048 59.904 54.364 60 ;
      RECT 0.048 60.672 54.364 60.768 ;
      RECT 0.048 61.44 54.364 61.536 ;
      RECT 0.048 62.208 54.364 62.304 ;
      RECT 0.048 62.976 54.364 63.072 ;
      RECT 0.048 63.744 54.364 63.84 ;
      RECT 0.048 64.512 54.364 64.608 ;
      RECT 0.048 65.28 54.364 65.376 ;
      RECT 0.048 66.048 54.364 66.144 ;
      RECT 0.048 66.816 54.364 66.912 ;
      RECT 0.048 67.584 54.364 67.68 ;
      RECT 0.048 68.352 54.364 68.448 ;
      RECT 0.048 69.12 54.364 69.216 ;
      RECT 0.048 69.888 54.364 69.984 ;
      RECT 0.048 70.656 54.364 70.752 ;
      RECT 0.048 71.424 54.364 71.52 ;
      RECT 0.048 72.192 54.364 72.288 ;
      RECT 0.048 72.96 54.364 73.056 ;
      RECT 0.048 73.728 54.364 73.824 ;
      RECT 0.048 74.496 54.364 74.592 ;
      RECT 0.048 75.264 54.364 75.36 ;
      RECT 0.048 76.032 54.364 76.128 ;
    END
  END VSS
  PIN VDD
    DIRECTION INOUT ;
    USE POWER ;
    PORT
      LAYER M4_m ;
      RECT 0.048 0.384 54.364 0.48 ;
      RECT 0.048 1.152 54.364 1.248 ;
      RECT 0.048 1.92 54.364 2.016 ;
      RECT 0.048 2.688 54.364 2.784 ;
      RECT 0.048 3.456 54.364 3.552 ;
      RECT 0.048 4.224 54.364 4.32 ;
      RECT 0.048 4.992 54.364 5.088 ;
      RECT 0.048 5.76 54.364 5.856 ;
      RECT 0.048 6.528 54.364 6.624 ;
      RECT 0.048 7.296 54.364 7.392 ;
      RECT 0.048 8.064 54.364 8.16 ;
      RECT 0.048 8.832 54.364 8.928 ;
      RECT 0.048 9.6 54.364 9.696 ;
      RECT 0.048 10.368 54.364 10.464 ;
      RECT 0.048 11.136 54.364 11.232 ;
      RECT 0.048 11.904 54.364 12 ;
      RECT 0.048 12.672 54.364 12.768 ;
      RECT 0.048 13.44 54.364 13.536 ;
      RECT 0.048 14.208 54.364 14.304 ;
      RECT 0.048 14.976 54.364 15.072 ;
      RECT 0.048 15.744 54.364 15.84 ;
      RECT 0.048 16.512 54.364 16.608 ;
      RECT 0.048 17.28 54.364 17.376 ;
      RECT 0.048 18.048 54.364 18.144 ;
      RECT 0.048 18.816 54.364 18.912 ;
      RECT 0.048 19.584 54.364 19.68 ;
      RECT 0.048 20.352 54.364 20.448 ;
      RECT 0.048 21.12 54.364 21.216 ;
      RECT 0.048 21.888 54.364 21.984 ;
      RECT 0.048 22.656 54.364 22.752 ;
      RECT 0.048 23.424 54.364 23.52 ;
      RECT 0.048 24.192 54.364 24.288 ;
      RECT 0.048 24.96 54.364 25.056 ;
      RECT 0.048 25.728 54.364 25.824 ;
      RECT 0.048 26.496 54.364 26.592 ;
      RECT 0.048 27.264 54.364 27.36 ;
      RECT 0.048 28.032 54.364 28.128 ;
      RECT 0.048 28.8 54.364 28.896 ;
      RECT 0.048 29.568 54.364 29.664 ;
      RECT 0.048 30.336 54.364 30.432 ;
      RECT 0.048 31.104 54.364 31.2 ;
      RECT 0.048 31.872 54.364 31.968 ;
      RECT 0.048 32.64 54.364 32.736 ;
      RECT 0.048 33.408 54.364 33.504 ;
      RECT 0.048 34.176 54.364 34.272 ;
      RECT 0.048 34.944 54.364 35.04 ;
      RECT 0.048 35.712 54.364 35.808 ;
      RECT 0.048 36.48 54.364 36.576 ;
      RECT 0.048 37.248 54.364 37.344 ;
      RECT 0.048 38.016 54.364 38.112 ;
      RECT 0.048 38.784 54.364 38.88 ;
      RECT 0.048 39.552 54.364 39.648 ;
      RECT 0.048 40.32 54.364 40.416 ;
      RECT 0.048 41.088 54.364 41.184 ;
      RECT 0.048 41.856 54.364 41.952 ;
      RECT 0.048 42.624 54.364 42.72 ;
      RECT 0.048 43.392 54.364 43.488 ;
      RECT 0.048 44.16 54.364 44.256 ;
      RECT 0.048 44.928 54.364 45.024 ;
      RECT 0.048 45.696 54.364 45.792 ;
      RECT 0.048 46.464 54.364 46.56 ;
      RECT 0.048 47.232 54.364 47.328 ;
      RECT 0.048 48 54.364 48.096 ;
      RECT 0.048 48.768 54.364 48.864 ;
      RECT 0.048 49.536 54.364 49.632 ;
      RECT 0.048 50.304 54.364 50.4 ;
      RECT 0.048 51.072 54.364 51.168 ;
      RECT 0.048 51.84 54.364 51.936 ;
      RECT 0.048 52.608 54.364 52.704 ;
      RECT 0.048 53.376 54.364 53.472 ;
      RECT 0.048 54.144 54.364 54.24 ;
      RECT 0.048 54.912 54.364 55.008 ;
      RECT 0.048 55.68 54.364 55.776 ;
      RECT 0.048 56.448 54.364 56.544 ;
      RECT 0.048 57.216 54.364 57.312 ;
      RECT 0.048 57.984 54.364 58.08 ;
      RECT 0.048 58.752 54.364 58.848 ;
      RECT 0.048 59.52 54.364 59.616 ;
      RECT 0.048 60.288 54.364 60.384 ;
      RECT 0.048 61.056 54.364 61.152 ;
      RECT 0.048 61.824 54.364 61.92 ;
      RECT 0.048 62.592 54.364 62.688 ;
      RECT 0.048 63.36 54.364 63.456 ;
      RECT 0.048 64.128 54.364 64.224 ;
      RECT 0.048 64.896 54.364 64.992 ;
      RECT 0.048 65.664 54.364 65.76 ;
      RECT 0.048 66.432 54.364 66.528 ;
      RECT 0.048 67.2 54.364 67.296 ;
      RECT 0.048 67.968 54.364 68.064 ;
      RECT 0.048 68.736 54.364 68.832 ;
      RECT 0.048 69.504 54.364 69.6 ;
      RECT 0.048 70.272 54.364 70.368 ;
      RECT 0.048 71.04 54.364 71.136 ;
      RECT 0.048 71.808 54.364 71.904 ;
      RECT 0.048 72.576 54.364 72.672 ;
      RECT 0.048 73.344 54.364 73.44 ;
      RECT 0.048 74.112 54.364 74.208 ;
      RECT 0.048 74.88 54.364 74.976 ;
      RECT 0.048 75.648 54.364 75.744 ;
      RECT 0.048 76.416 54.364 76.512 ;
    END
  END VDD
  OBS
    LAYER M1_m ;
    RECT 0 0 54.412 76.516 ;
    LAYER M2_m ;
    RECT 0 0 54.412 76.516 ;
    LAYER M3_m ;
    RECT 0 0 54.412 76.516 ;
  END
END ht_asap7_leon3vtabus_vta_q_512x128_upper

END LIBRARY
